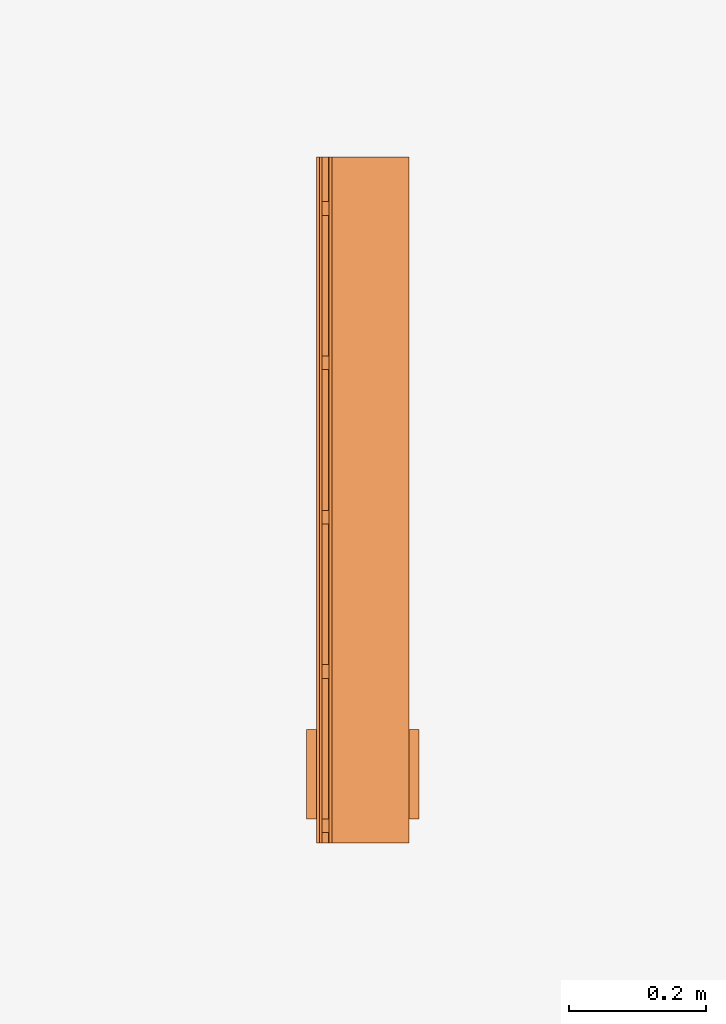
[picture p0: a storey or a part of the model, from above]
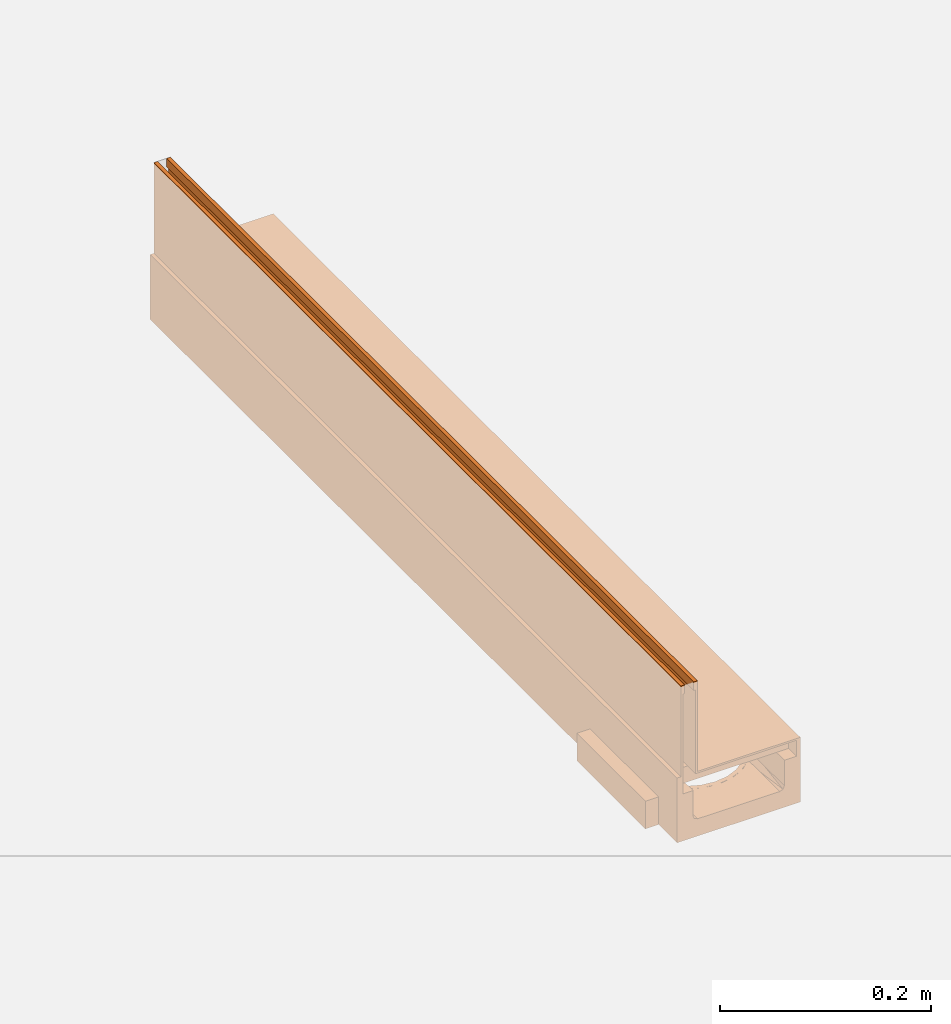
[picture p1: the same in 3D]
Properties of the parts of a building model (IFC2X3)

# File
Description: ViewDefinition [CoordinationView]
File name: 24076.ifc
Time: 2013-10-30T12:01:17
Written by: Autodesk Revit 2013
Made in: 20120221_2030(x64)

# IfcProject, Project Number
LongName: Project Name; Phase: Project Status

# IfcSite, Default
RefLatitude: 42, 21, 30, 344238; RefLongitude: -71, -3, -35, -194702; RefElevation: 0 mm

# IfcBuilding
Pset_BuildingCommon - NumberOfStoreys: 1
Other - Project Status: Project Status; Project Address: ## Street City, State Zip; Client Name: Owner; Project Name: Project Name; Project Number: Project Number; Project Issue Date: Issue Date

# IfcBuildingStorey, Level 1
LongName: Level 1; Elevation: 0 mm
Constraints - Elevation Base: 0; Elevation: 0 mm
Graphics - Symbol at End 2 Default: yes; Symbol: M_Level Head - Circle: M_Level Head - Circle; Line Pattern: Center; Symbol at End 1 Default: no; Line Weight: 1; Color: 0
Identity Data - Building Story: yes; Structural: no; Name: Level 1
Dimensions - Computation Height: 0 mm

# IfcBuildingElementProxy: 24076 - No 075V Constant Depth Outlet Channel - 1000mm LG – Invert Depth 55mm, Civil-Drainage-Channel-ACO-MultiDrain-M100DS-Brickslot-Channel-System:24076 - No 075V Constant Depth Outlet Channel - 1000mm LG – Invert Depth 55mm:24076 - No 075V Constant Depth Outlet Channel - 1000mm LG – Invert Depth 55mm:196059
In: Level 1
Material: Stainless Steel (F), Plastic, Opaque Black, Vienite® Synthetic Resin Concrete
Construction - 23476_Load Class C250 & D400_Brickslot Grating_Stainless Steel_500mm Long: no; 23404_Universal Endcap (Female End): no; 23404_Universal Endcap (Male End): no; 23475_Load Class C250 & D400_Brickslot Grating_Stainless Steel_1000mm Long: yes; 23477_Load Class C250 & D400_Brickslot_Access Unit_Stainless Steel_500mm Long: no; 23410_Sump Unit: no; Shallow Depth Channel: no; Constant Depth Channel: no; Constant Depth Junction Channel: no; Shallow Depth Channel with seal: yes
Dimensions - Brickslot Void Length: 1000 mm; EndCap Position: 1000 mm; Length: 1000 mm; Custom_Void_length: 0 mm; Brickslot Access Unit Void Depth: -6500 mm; Brickslot Access Unit Void Bottom Depth: -6605 mm; FloorCut_Length: -1000 mm; Brickslot Void Depth: 0 mm; Volume: 4830973 mm3; InvDepth: 80 mm; GratingLength: -1000 mm; FloorCut_Width: 135 mm; Brickslot Access Unit Floor Cut Length: 500 mm; Depth: 150 mm; FloorCut_Depth: 75 mm; ShallowOverallDepth: 75 mm; Floor Cut Gap: 105 mm; ShallowInvDepth: 55 mm; Length Drain: -1000 mm; EndCap_Height: 75 mm
Constraints - Moves With Nearby Elements: no; Level: Level: Level 1
Phasing - Phase Created: New Construction
Pset_BuildingElementProxyCommon - Reference: 24076 - No 075V Constant Depth Outlet Channel - 1000mm LG – Invert Depth 55mm
Data - Concrete Surround Volume - Load Class D 400 - Concrete Pavement: 0.14m³/m 0.14m³/m; Concrete Surround Volume - Load Class B 125 - C 250 - Concrete Pavement: 0.09m³/m; Installation - Concrete Grade: Refer to brochure; Channel C.S.A: 0.0034m²; Product Dimensions: 1000mm x 135mm x 75mm (LxWxH); ACO Hydraulic Design Software: http://www.acodesign.co.uk; Load Class: A 15 - D 400; Concrete Surround Volume - Load Class A 15 - Concrete Pavement: 0.05m³/m; Pre-formed Outlet Ø: 110mm; Hydraulic Performance: http://www.aco.co.uk/download.php?id=173; Product Weight: 10.5 Kg; Invert Depth: 55mm; Product Standard: BS EN 1433:2002, CE marked 0.0034m² 55mm
Identity Data - Watermarked With: BIM Manager Premium Suite; Address: ACO Business Park, Hitchin Road, Shefford, Bedfordshire, United Kingdom SG17 5TE; Assembly Description: Rain Water Drainage; Installation guidelines: http://www.aco.co.uk/download.php?id=173; Assembly Code: D2040; Model: ACO MultiDrain MDS Brickslot- M100DS; Product brochure: http://www.aco.co.uk/download.php?id=173; Type Comments: ACO MultiDrain M100DS No 075V Constant Depth Shallow Outlet Channel 1000mm Long; Telephone: +44 (0)1462 816666; e-mail Sales: customersupport@aco.co.uk; Watermarked By: www.aco.co.uk; Cost: 0; Fax: +44 (0)1462 815895; Price: POA - contact ACO; e-mail Technical: technical@aco.co.uk; Product Page URL: http://www.aco.co.uk/product_detail.php?id=58; URL: www.aco.co.uk; Product Code: 24076; OmniClass Number: 23.70.50.24; Watermark 1: This file is the property of ACO Technologies PLC; Manufacturer: ACO Technologies plc - ACO Water Management Division; Model Description: Channel drainage system; OmniClass Title: Rainwater Removal; Maintenance guidelines: http://www.aco.co.uk/download.php?id=173; Watermark 2: This file is water marked and users are prohibited to reproduce, adapt, distribute this information
Materials and Finishes - Edge Rail Material: Stainless Steel Grade 304; Edge Rail Colour: Self; Channel Colour: Brown; Channel Material: Vienite® Synthetic Resin Concrete
General - SerialNumber: 0; TagNumber: 0
Green Building Properties - Edge Rail Recyclable: Fully recyclable; Channel Recycled Material Content: 20% minimum; Channel Recyclable: Fully recyclable; Edge Rail Recycled Material Content: Between 40% - 90%
Model Properties - Brickslot Access Unit Product code 23477: Load Class C250/D400 - Brickslot Access Unit Stainless Steel - 500mm long x 105mm high -10mm Slot- Intake area - 1000mm²/m - 6.4 Kg; Brickslot Grating Product code 23476: Load Class C250/D400 - Brickslot Stainless Steel - 500mm long x 105mm high -10mm Slot- Intake area - 1000mm²/m - 3.3 Kg; Brickslot Grating Product code 23475: Load Class C250/D400 - Brickslot Stainless Steel - 1000mm long x 105mm high -10mm Slot- Intake area - 1000mm²/m - 6.6 Kg; End Cap Product code 23404: No 306 Universl End Cap - 135mm wide x 300mm long - Spigot Ø110mm x 50mm long - Silver - Polypropylene - 0.16kg
Other - Created By: www.aco.co.uk; Revision: 1

# IfcOpeningElement: Recess (2)
In: Level 1
Dimensions - Volume: 9987985000 mm3; Area: 25000000 mm2; Thickness: 400 mm; Perimeter: 20000 mm
Phasing - Phase Created: New Construction
Constraints - Level: Level: Level 1; Related to Mass: no; Height Offset From Level: 0 mm; Room Bounding: yes
Structural - Enable Analytical Model: no; Structural: no
Analytical Properties - Absorptance: 0.1; Roughness: 1; Thermal mass: 543920; Thermal Resistance (R): 0.477897; Heat Transfer Coefficient (U): 2.0925
Graphics - Coarse Scale Fill Color: 0
Construction - Default Thickness: 400 mm; Function: 0
Materials and Finishes - Structural Material: Earth

# IfcSlab: Floor:Generic Floor - 400mm, Floor:Generic Floor - 400mm:193825
In: Level 1
PredefinedType: FLOOR; Material: Earth 400 mm
Dimensions - Volume: 9987985000 mm3; Area: 25000000 mm2; Thickness: 400 mm; Perimeter: 20000 mm
Phasing - Phase Created: New Construction
Constraints - Level: Level: Level 1; Related to Mass: no; Height Offset From Level: 0 mm; Room Bounding: yes
Structural - Enable Analytical Model: no; Structural: no
Pset_SlabCommon - Reference: Generic Floor - 400mm; IsExternal: no; LoadBearing: yes
Analytical Properties - Absorptance: 0.1; Roughness: 1; Thermal mass: 543920; Thermal Resistance (R): 0.477897; Heat Transfer Coefficient (U): 2.0925
Graphics - Coarse Scale Fill Color: 0
Construction - Default Thickness: 400 mm; Function: 0
Materials and Finishes - Structural Material: Earth
